VERSION 5.7 ;
  NOWIREEXTENSIONATPIN ON ;
  DIVIDERCHAR "/" ;
  BUSBITCHARS "[]" ;
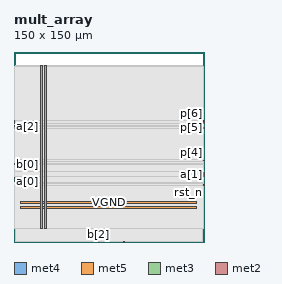
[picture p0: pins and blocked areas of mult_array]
MACRO mult_array
  CLASS BLOCK ;
  FOREIGN mult_array ;
  ORIGIN 0.000 0.000 ;
  SIZE 150.000 BY 150.000 ;
  PIN VGND
    DIRECTION INOUT ;
    USE GROUND ;
    PORT
      LAYER met4 ;
        RECT 24.340 10.640 25.940 138.960 ;
    END
    PORT
      LAYER met5 ;
        RECT 5.520 30.030 144.440 31.630 ;
    END
  END VGND
  PIN VPWR
    DIRECTION INOUT ;
    USE POWER ;
    PORT
      LAYER met4 ;
        RECT 21.040 10.640 22.640 138.960 ;
    END
    PORT
      LAYER met5 ;
        RECT 5.520 26.730 144.440 28.330 ;
    END
  END VPWR
  PIN a[0]
    DIRECTION INPUT ;
    USE SIGNAL ;
    ANTENNAGATEAREA 0.213000 ;
    PORT
      LAYER met3 ;
        RECT 0.000 47.640 0.600 48.240 ;
    END
  END a[0]
  PIN a[1]
    DIRECTION INPUT ;
    USE SIGNAL ;
    ANTENNAGATEAREA 0.213000 ;
    PORT
      LAYER met3 ;
        RECT 149.400 53.080 150.000 53.680 ;
    END
  END a[1]
  PIN a[2]
    DIRECTION INPUT ;
    USE SIGNAL ;
    ANTENNAGATEAREA 0.213000 ;
    PORT
      LAYER met3 ;
        RECT 0.000 91.160 0.600 91.760 ;
    END
  END a[2]
  PIN a[3]
    DIRECTION INPUT ;
    USE SIGNAL ;
    ANTENNAGATEAREA 0.213000 ;
    PORT
      LAYER met3 ;
        RECT 0.000 95.240 0.600 95.840 ;
    END
  END a[3]
  PIN b[0]
    DIRECTION INPUT ;
    USE SIGNAL ;
    ANTENNAGATEAREA 0.213000 ;
    PORT
      LAYER met3 ;
        RECT 0.000 61.240 0.600 61.840 ;
    END
  END b[0]
  PIN b[1]
    DIRECTION INPUT ;
    USE SIGNAL ;
    ANTENNAGATEAREA 0.213000 ;
    PORT
      LAYER met3 ;
        RECT 0.000 89.800 0.600 90.400 ;
    END
  END b[1]
  PIN b[2]
    DIRECTION INPUT ;
    USE SIGNAL ;
    ANTENNAGATEAREA 0.213000 ;
    PORT
      LAYER met2 ;
        RECT 66.330 0.000 66.610 0.280 ;
    END
  END b[2]
  PIN b[3]
    DIRECTION INPUT ;
    USE SIGNAL ;
    ANTENNAGATEAREA 0.213000 ;
    PORT
      LAYER met3 ;
        RECT 149.400 54.440 150.000 55.040 ;
    END
  END b[3]
  PIN clk
    DIRECTION INPUT ;
    USE SIGNAL ;
    ANTENNAGATEAREA 0.852000 ;
    PORT
      LAYER met3 ;
        RECT 0.000 93.880 0.600 94.480 ;
    END
  END clk
  PIN p[0]
    DIRECTION OUTPUT ;
    USE SIGNAL ;
    ANTENNADIFFAREA 0.702900 ;
    PORT
      LAYER met3 ;
        RECT 0.000 50.360 0.600 50.960 ;
    END
  END p[0]
  PIN p[1]
    DIRECTION OUTPUT ;
    USE SIGNAL ;
    ANTENNADIFFAREA 0.702900 ;
    PORT
      LAYER met3 ;
        RECT 0.000 49.000 0.600 49.600 ;
    END
  END p[1]
  PIN p[2]
    DIRECTION OUTPUT ;
    USE SIGNAL ;
    ANTENNADIFFAREA 0.702900 ;
    PORT
      LAYER met2 ;
        RECT 86.570 0.000 86.850 0.280 ;
    END
  END p[2]
  PIN p[3]
    DIRECTION OUTPUT ;
    USE SIGNAL ;
    ANTENNADIFFAREA 0.702900 ;
    PORT
      LAYER met3 ;
        RECT 149.400 51.720 150.000 52.320 ;
    END
  END p[3]
  PIN p[4]
    DIRECTION OUTPUT ;
    USE SIGNAL ;
    ANTENNADIFFAREA 0.702900 ;
    PORT
      LAYER met3 ;
        RECT 149.400 63.960 150.000 64.560 ;
    END
  END p[4]
  PIN p[5]
    DIRECTION OUTPUT ;
    USE SIGNAL ;
    ANTENNADIFFAREA 0.702900 ;
    PORT
      LAYER met3 ;
        RECT 149.400 89.800 150.000 90.400 ;
    END
  END p[5]
  PIN p[6]
    DIRECTION OUTPUT ;
    USE SIGNAL ;
    ANTENNADIFFAREA 0.702900 ;
    PORT
      LAYER met3 ;
        RECT 149.400 95.240 150.000 95.840 ;
    END
  END p[6]
  PIN p[7]
    DIRECTION OUTPUT ;
    USE SIGNAL ;
    ANTENNADIFFAREA 0.702900 ;
    PORT
      LAYER met3 ;
        RECT 149.400 93.880 150.000 94.480 ;
    END
  END p[7]
  PIN rst_n
    DIRECTION INPUT ;
    USE SIGNAL ;
    ANTENNAGATEAREA 0.213000 ;
    PORT
      LAYER met3 ;
        RECT 149.400 44.920 150.000 45.520 ;
    END
  END rst_n
  OBS
      LAYER nwell ;
        RECT 5.330 10.795 144.630 138.910 ;
      LAYER li1 ;
        RECT 5.520 10.795 144.440 138.805 ;
      LAYER met1 ;
        RECT 0.990 10.640 148.510 138.960 ;
      LAYER met2 ;
        RECT 1.010 0.560 148.490 138.905 ;
        RECT 1.010 0.280 66.050 0.560 ;
        RECT 66.890 0.280 86.290 0.560 ;
        RECT 87.130 0.280 148.490 0.560 ;
      LAYER met3 ;
        RECT 0.600 96.240 149.400 138.885 ;
        RECT 1.000 93.480 149.000 96.240 ;
        RECT 0.600 92.160 149.400 93.480 ;
        RECT 1.000 90.800 149.400 92.160 ;
        RECT 1.000 89.400 149.000 90.800 ;
        RECT 0.600 64.960 149.400 89.400 ;
        RECT 0.600 63.560 149.000 64.960 ;
        RECT 0.600 62.240 149.400 63.560 ;
        RECT 1.000 60.840 149.400 62.240 ;
        RECT 0.600 55.440 149.400 60.840 ;
        RECT 0.600 51.360 149.000 55.440 ;
        RECT 1.000 51.320 149.000 51.360 ;
        RECT 1.000 47.240 149.400 51.320 ;
        RECT 0.600 45.920 149.400 47.240 ;
        RECT 0.600 44.520 149.000 45.920 ;
        RECT 0.600 10.715 149.400 44.520 ;
  END
END mult_array
END LIBRARY

